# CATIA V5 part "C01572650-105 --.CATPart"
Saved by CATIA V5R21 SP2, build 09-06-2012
Part number: C01572650-105
Revision: ---
Description: PROPRIETARY NOTICE (do not delete / modify)  ***************************************************************************************************  LA SOCIETE EN COMMANDITE  AIRBUS CANADA  ("AIRBUS CANADA")  PAR  L'INTERMEDIAIRE  DE  SES  DIVISIONS  ET/OU  FILIALES  CORPORATIVES,  FOURNIT  LES PRESENTES  INFORMATIONS  AU  GOUVERNEMENT  A  TITRE CONFIDENTIEL. CES  INFORMATIONS ONT UNE TENEUR CONFIDENTIELLE,  AVEC DROITS DE PROPRIETE,  ET NOUS LES CONSIDERONS  EXCLUS  DE   L'APPLICATION  DE  LA LOI SUR L'ACCES A L'INFORMATION  (CANADA),  LES  LOIS  SUR  L'ACCES  A  L'INFORMATION  EUROPEENNES,  LE FREEDOM OF INFORMATION ACT (ETATS-UNIS) ET D'AUTRES LOIS SEMBLABLES. ELLES  PEUVENT  AUSSI  CONSTITUER DES SECRETS INDUSTRIELS DE NOTRE SOCIETE OU DE TIERCES PARTIES. LA DIVULGATION  PUBLIQUE  DE CES  INFORMATIONS NUIRAIT A AIRBUS CANADA OU A DES TIERCES PARTIES.  CES INFORMATIONS PEUVENT EGALEMENT CONTENIR  DES DONNEES QUI SONT CONTROLEE PAR DES LOIS DE CONTROLE DES EXPORTATIONS DU CANADA, L’EUROPE OU LES  ETATS-  UNIS. TOUTE EXPORTATION OU REEXPORTATION DE DONNEES CONTROLEES SANS AUTORISATION EST STRICTEMENT INTERDITE.  TOUTE INTENTION DE LES DIVULGUER EN TOUT OU EN PARTIE DEVRA ETRE SIGNIFIEE A L'AVANCE ET PAR ECRIT AU VICE-  PRESIDENT, SERVICES JURIDIQUES ET CONFORMITE ET SECRETAIRE CORPORATIF D'AIRBUS CANADA.    AIRBUS CANADA LIMITED PARTNERSHIP  ("AIRBUS CANADA"),  BY ITS AFFILIATES AND/OR SUBSIDIARIES, PROVIDES THIS  INFORMATION TO THE GOVERNMENT IN CONFIDENCE. THIS IS PROPRIETARY CONFIDENTIAL INFORMATION WHICH WE CONSIDER  EXCLUDED  FROM  THE  APPLICATION OF THE ACCESS TO INFORMATION ACT (CANADA),  THE FREEDOM OF INFORMATION ACT  (U.S.A.),  THE ACCESS TO INFORMATION LAWS IN EUROPE, AND OTHER SIMILAR LEGISLATION. AND MAY ALSO CONSTITUTE  TRADE SECRETS OF OUR  COMPANY OR THIRD PARTIES.  PUBLIC  RELEASE  OF  THIS INFORMATION  WOULD BE HARMFUL TO  AIRBUS CANADA OR THIRD PARTIES.  THIS  INFORMATION  MAY  ALSO  CONTAIN DATA THAT IS CONTROLLED BY CANADIAN,  EUROPEAN, OR U.S.A. EXPORT CONTROL LAWS. ANY UNAUTHORIZED EXPORT OR RE-EXPORT OF ANY EXPORT CONTROLLED DATA  IS STRICTLY PROHIBITED  ANY INTENTION TO DISCLOSE SUCH INFORMATION,  OR  PART THEREOF,  MUST BE NOTIFIED IN  ADVANCE AND IN WRITING TO THE VICE PRESIDENT, LEGAL AND COMPLIANCE AND CORPORATE SECRETARY OF AIRBUS CANADA.        LES RENSEIGNEMENTS,  LES DONNEES  ET  DESSINS  TECHNIQUES  DIVULGUES  DANS  LES PRESENTES SONT LA PROPRIETE  EXCLUSIVE DE LA SOCIETE EN COMMANDITE AIRBUS CANADA ("AIRBUS CANADA") OU COMPORTENT DES DROITS DE PROPRIETE  APPARTENANT  A  AUTRUI ET NE PEUVENT ETRE DIVULGUES  A  QUICONQUE  NI  UTILISES PAR QUI QUE CE SOIT SANS LE  CONSENTEMENT  ECRIT  D’AIRBUS  CANADA.  LE DETENTEUR DES  PRESENTES  S'ENGAGE, DANS TOUTES CIRCONSTANCES, A  GARDER CONFIDENTIELS LES DONNEES ET DESSINS TECHNIQUES QU'ELLES CONTIENNENT.   CE QUI PRECEDE NE S'APPLIQUE  PAS  AUX PERSONNES  QUI  ONT DES DROITS DE PROPRIETE SUR CES RENSEIGNEMENTS,  DONNEES TECHNIQUES ET DESSINS  DANS LA MESURE OU CES DROITS EXISTENT.    THE INFORMATION,  TECHNICAL DATA  AND  DESIGNS DISCLOSED HEREIN ARE THE EXCLUSIVE PROPERTY OF AIRBUS CANADA  LIMITED PARTNERSHIP  ("AIRBUS CANADA")  OR  CONTAIN PROPRIETARY RIGHTS OF OTHERS  AND ARE NOT TO BE USED OR  DISCLOSED  TO  OTHERS WITHOUT THE WRITTEN CONSENT OF AIRBUS CANADA.  THE RECIPIENT OF THIS DOCUMENT, BY ITS  RETENTION  AND  USE  AGREES TO  HOLD  IN  CONFIDENCE  THE  TECHNICAL DATA AND DESIGNS CONTAINED HEREIN. THE  FOREGOING SHALL NOT APPLY TO PERSONS HAVING PROPRIETARY RIGHTS TO SUCH INFORMATION,  TECHNICAL DATA OR SUCH  DESIGNS TO THE EXTENT THAT SUCH RIGHTS EXIST.    Copyright 2020 Airbus Canada Limited Partnership. All Rights Reserved.  ***********************************
Property "Title": "BODY, ROD, SPRING, SELF OPEN, OWE"
Property "Dataset Type": "DETAIL"
Property "Supplier Name And CAGE Code": "AIRBUS CANADA LIMITED PARTNERSHIP L0J48"
Property "Major Supplier Code": "LP"
Property "3D Only": "N/A"
Property "Material Form": "BAR - ROUND"
Property "Finish Code": "A151"
Property "PCCN": "2"
Property "Organization": "DESIGN"
Property "Design Authority Program": "BD-500"
Property "Color Coded": "N/A"
Property "Thickness": 0
Property "Inside Diameter": 0
Property "Outside Diameter": 2
Property "Length": 0
Property "Width": 0
Property "Wall": 0
Property "Wire Gauge": "-"
Property "Alloy": "7075"
Property "Final Condition": "T73"
Property "Density": "N/A"
Property "Form": "N/A"
Property "Grade/Composition": "N/A"
Property "Material Class": "N/A"
Property "Mesh Cell Size": "N/A"
Property "Standard Spec Die": "N/A"
Property "Type": "N/A"
Property "Style": "N/A"
Property "MFG Process": "MACHINED"
Property "Material Specification Production": "AMS-QQ-A-200/11"
Property "Material Description Production": "ALUMINUM ALLOY"
Property "Dimensions": "DIMENSIONS ARE IN INCHES"
Property "Roughness": "ALL MACHINED SURFACES 125 Ra MAX"
Property "Eng. Tolerances": "LINEAR .XX= +/-.03; .XXX= +/-.010; ANGULAR= +/-0.5 DEG"
Property "Tool Design Tolerances": "LINEAR .X= +/-.06; .XX= +/-.015; .XXX= +/-.005; .XXXX= +/-.001; ANGULAR= +/-0.5 DEG"
Property "Project": "BA"
Publications: "PartBody"
Material "AL-7075-BAR": density 2795.67 kg/m3, Young's modulus 7.17055e+10 Pa, Poisson ratio 0.33
Bounding box of the stored display mesh (mm): x -20.822 to 20.822, y -20.827 to 20.827, z -11.43 to 117.348
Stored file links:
  C:\Users\CQQZ006\Desktop\A220钢钛件\舱门\C01572650-105\C01572650-105 --.CATPart

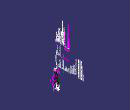
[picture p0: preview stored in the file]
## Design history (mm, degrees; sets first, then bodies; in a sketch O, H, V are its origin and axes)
AxisSystem1 "Absolute Axis System": origin (0, 0, 0), X (1, 0, 0), Y (0, 1, 0), Z (0, 0, 1)
Part_3D_Annotations1 "CATTPSSet"
Set1 "Geometrical Set for 3D Annotations"
  Set2 "No Show Geometry"
    Extract1 "DATUM_A": ExtractElem face of Shaft1 from Sketch1.L7
    MultiExtract1 "DATUM_B": ListOfMultiExtractConstraints (MultiExtractConstraint face of Pocket1 from Sketch2.L2; MultiExtractConstraint face of Pocket1 from Sketch2.L8)
    Extract2 "DATUM_C": ExtractElem face of Hole1
    Extract3: ExtractElem face of Shaft1 from Sketch1.L4
    Extract4: ExtractElem face of Shaft1 from Sketch1.L13
    MultiExtract2: ListOfMultiExtractConstraints (MultiExtractConstraint face of Shaft1 from Sketch1.A6; MultiExtractConstraint face of Shaft1 from Sketch1.L7)
    Extract5: ExtractElem face of Chamfer2
    Extract6: ExtractElem face of Shaft1 from Sketch1.L2
    Join1: Elements (Extract6; Extract4)
    MultiExtract3: ListOfMultiExtractConstraints (MultiExtractConstraint face of Shaft1 from Sketch1.L8; MultiExtractConstraint face of Shaft1 from Sketch1.L5; MultiExtractConstraint face of Shaft1 from Sketch1.L9; MultiExtractConstraint face of Shaft1 from Sketch1.L6; MultiExtractConstraint face of Shaft1 from Sketch1.A3; MultiExtractConstraint face of Shaft1 from Sketch1.L11; MultiExtractConstraint face of Pocket1 from Sketch2.L1; MultiExtractConstraint face of Fillet1; MultiExtractConstraint face of Shaft1 from Sketch1.A4; MultiExtractConstraint face of Fillet1; MultiExtractConstraint face of Pocket1 from Sketch2.L7; MultiExtractConstraint face of Shaft1 from Sketch1.A4)
  Set3 "Surfaces for 3D Annotations"
    Set4 "CHANGE INFORMATION_GS"
      Offset1: Offset MultiExtract3, Length 0.0254
Body1 (main body)
  Sketch1 on yz-plane, origin (0, 0, 0), H (0, 1, 0), V (0, 0, 1)
    construction circle A1 centre (0, 0) radius 7.1539
    arc A2 centre (0, 0) radius 11.43 from (-11.43, 0) to (0, -11.43) ccw
    line L1 (-8.255, 117.348) -> (-6.35, 117.348)
    line L2 (-5.5563, 15.0951) -> (0, 11.8872)
    line L3 (0, 11.8872) -> (0, -11.43)
    line L4 (-8.255, 117.348) -> (-8.255, 15.9512)
    point P3 (0, 11.8872)
    line L5 (-20.828, 14.4272) -> (-20.828, 12.6492)
    arc A3 centre (-16.51, 9.6012) radius 2.286 from (-15.564, 11.6823) to (-16.51, 11.8872) ccw
    point P4 (-16.51, 9.6012)
    line L6 (-20.066, 11.8872) -> (-16.51, 11.8872)
    line L7 (-6.35, 117.348) -> (-6.35, 76.708)
    line L8 (-20.828, 14.4272) -> (-9.779, 14.4272)
    line L9 (-20.828, 12.6492) -> (-20.066, 11.8872)
    point P9 (-20.828, 12.6492)
    line L10 (-11.43, 0) -> (-11.43, 8.3312)
    arc A4 centre (-13.716, 8.3312) radius 2.286 from (-12.77, 10.4123) to (-11.43, 8.3312) cw
    point P12 (-13.716, 8.3312)
    line L11 (-15.564, 11.6823) -> (-12.77, 10.4123)
    axis line L12 (0, -33.2978) -> (0, 47.9825)
    arc A5 centre (-9.779, 15.9512) radius 1.524 from (-9.779, 14.4272) to (-8.255, 15.9512) ccw
    line L13 (-5.5563, 74.6565) -> (-5.5563, 15.0951)
    arc A6 centre (-3.302, 76.708) radius 3.048 from (-6.35, 76.708) to (-5.5563, 74.6565) ccw
    point P20 (-3.302, 76.708)
    radius A1 = 7.1539
    radius A2 = 11.43
    distance L5 L3 = 20.828
    radius A3 = 2.286
    angle L2 L3 = 60
    distance P3 H = 11.8872
    distance L7 L4 = 1.905 (reference)
    distance L8 L1 = 102.9208
    distance L8 H = 14.4272
    distance L6 L8 = 2.54
    angle L5 L9 = 45
    distance P9 L6 = 0.762
    radius A4 = 2.286
    distance P4 L3 = 16.51
    distance P12 L6 = 3.556
    "Radius" L4 L12 = 8.255
    radius A5 = 1.524
    "Radius" L7 L12 = 6.35
    "Radius" L13 L12 = 5.5563
    radius A6 = 3.048
    distance P20 L1 = 40.64
    horizontal: L1 H, L8 H, L6 H
    vertical: L3 V, L4 V, L5 V, L7 V, L10 V, L13 V
    coincidence: L3 V, L12 V
    tangency: L6 A3, L10 A2, A4 L10, L11 A4, A3 L11, A5 L8, A5 L4, A6 L7
  Shaft1: profile Sketch1, axis Sketch1.L3, angle 360
  Body2
    Sketch2 on zx-plane, origin (0, 0, 0), H (-1, 0, 0), V (0, 0, 1)
      point P1 (-25.4, 11.1252)
      line L1 (-25.4, 11.1252) -> (-2.794, 11.1252)
      line L2 (-2.794, 11.1252) -> (-2.794, -25.4)
      line L3 (-2.794, -25.4) -> (-25.4, -25.4)
      line L4 (-25.4, -25.4) -> (-25.4, 11.1252)
      point P2 (-2.794, 11.1252)
      point P3 (-2.794, -25.4)
      point P4 (-25.4, -25.4)
      point P5 (25.4, -25.4)
      point P6 (2.794, -25.4)
      line L5 (2.794, -25.4) -> (25.4, -25.4)
      point P7 (25.4, 11.1252)
      line L6 (25.4, -25.4) -> (25.4, 11.1252)
      point P8 (2.794, 11.1252)
      line L7 (25.4, 11.1252) -> (2.794, 11.1252)
      line L8 (2.794, 11.1252) -> (2.794, -25.4)
      construction line L9 (-36.2939, 14.4272) -> (33.499, 14.4272)
      reference intersected line E1 through (0, 14.4272) direction (-1, 0) from face of Shaft1 from Sketch1.L8
      distance L4 V = 25.4
      distance L3 H = 25.4
      distance L2 L8 = 5.588
      distance L7 L9 = 3.302
      horizontal: L1 H, L3 H, L9 H
      vertical: L2 V, L4 V
      symmetry: P4 P5 V, P3 P6 V, L3 L5 V, P1 P7 V, L4 L6 V, P2 P8 V, L1 L7 V, L2 L8 V
      coincidence: L9 E1
    Pocket1: profile Sketch2, direction (0, -1, 0), length 25.4, mirrored extent
    Fillet1: radius 2.286, on edge [face of Pocket1 from Sketch2.L2 | face of Pocket1 from Sketch2.L1]; edge [face of Pocket1 from Sketch2.L7 | face of Pocket1 from Sketch2.L8]
  Assemble1: tool Body2
  Sketch3 on face of Pocket1 from Sketch2.L2, origin (2.794, 0, 0), H (0, 1, 0), V (0, 0, 1)
    point P1 (0, 0)
    reference projected point E1 (0, 0) from edge
    coincidence: P1 E1
  Hole1: placed by Sketch3, at (2.794, 0, 0) direction (-1, 0, 0), diameter 14.2875, depth 10
  Chamfer1: length 0.7874, second length 0.7874, on edge [face of Pocket1 from Sketch2.L2 | face of Hole1]; edge [face of Hole1 | face of Pocket1 from Sketch2.L8]
  Body3
    Sketch4 on zx-plane, origin (0, 0, 0), H (-1, 0, 0), V (0, 0, 1)
      projected line E1 (2.794, 0) -> (2.794, 8.3312) from edge [face of Pocket1 from Sketch2.L8 | face of Shaft1 from Sketch1.L10]
      projected line E2 (2.794, 0) -> (2.794, 11.1252) from edge [face of Pocket1 from Sketch2.L8 | face of Shaft1 from Sketch1.L10]
      projected line E3 (5.08, 11.1252) -> (14.3384, 11.1252) from edge [face of Pocket1 from Sketch2.L7 | face of Shaft1 from Sketch1.L11]
      projected line E4 (2.794, 11.1252) -> (14.3384, 11.1252) from edge [face of Pocket1 from Sketch2.L7 | face of Shaft1 from Sketch1.L11]
      point P5 (2.794, 11.1252)
      line L1 (17.6061, -5.932) -> (-4.1698, 15.8439)
      point P7 (-4.1698, 15.8439)
      axis line L2 (24.4605, -10.5413) -> (-12.6405, 26.5597)
      line L3 (-4.1698, 15.8439) -> (-3.0473, 16.9665)
      point P10 (-4.1698, 15.8439)
      point P11 (-3.0473, 16.9665)
      line L4 (17.6061, -5.932) -> (18.7287, -4.8095)
      point P12 (18.7287, -4.8095)
      angle L2 E3 = 45
      distance L1 L2 = 1.5875
      coincidence: L2 P5, P10 L1, P11 L2, P12 L2, P7 P10
      perpendicularity: L3 L2
      parallelism: L4 L3
    Groove1: profile Sketch4, axis Sketch4.L2, angle 360
  Assemble2: tool Body3
  Chamfer2: length 6.35, second length 0.762, on edge [face of Shaft1 from Sketch1.L4 | face of Shaft1 from Sketch1.L1]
